VERSION 5.8 ;
BUSBITCHARS "[]" ;
DIVIDERCHAR "/" ;
UNITS
    DATABASE MICRONS 1000 ;
END UNITS

VIA PLL_COUNTER_DCO_PHYS_via1_2_1000_160_1_5_200_200
  VIARULE MET2_MET1 ;
  CUTSIZE 0.09 0.09 ;
  LAYERS MET1 VIA1 MET2 ;
  CUTSPACING 0.11 0.11 ;
  ENCLOSURE 0.04 0.035 0.005 0.04 ;
  ROWCOL 1 5 ;
END PLL_COUNTER_DCO_PHYS_via1_2_1000_160_1_5_200_200

VIA PLL_COUNTER_DCO_PHYS_via2_3_1000_160_1_5_200_200
  VIARULE MET3_MET2 ;
  CUTSIZE 0.09 0.09 ;
  LAYERS MET2 VIA2 MET3 ;
  CUTSPACING 0.11 0.11 ;
  ENCLOSURE 0.005 0.04 0.04 0.005 ;
  ROWCOL 1 5 ;
END PLL_COUNTER_DCO_PHYS_via2_3_1000_160_1_5_200_200

VIA PLL_COUNTER_DCO_PHYS_via3_4_1000_160_1_5_200_200
  VIARULE MET4_MET3 ;
  CUTSIZE 0.09 0.09 ;
  LAYERS MET3 VIA3 MET4 ;
  CUTSPACING 0.11 0.11 ;
  ENCLOSURE 0.04 0.005 0.055 0.04 ;
  ROWCOL 1 5 ;
END PLL_COUNTER_DCO_PHYS_via3_4_1000_160_1_5_200_200

VIA PLL_COUNTER_DCO_PHYS_via4_5_1000_1000_5_5_200_200
  VIARULE MET5_MET4 ;
  CUTSIZE 0.09 0.09 ;
  LAYERS MET4 VIA4 MET5 ;
  CUTSPACING 0.11 0.11 ;
  ENCLOSURE 0.055 0.02 0.04 0.055 ;
  ROWCOL 5 5 ;
END PLL_COUNTER_DCO_PHYS_via4_5_1000_1000_5_5_200_200

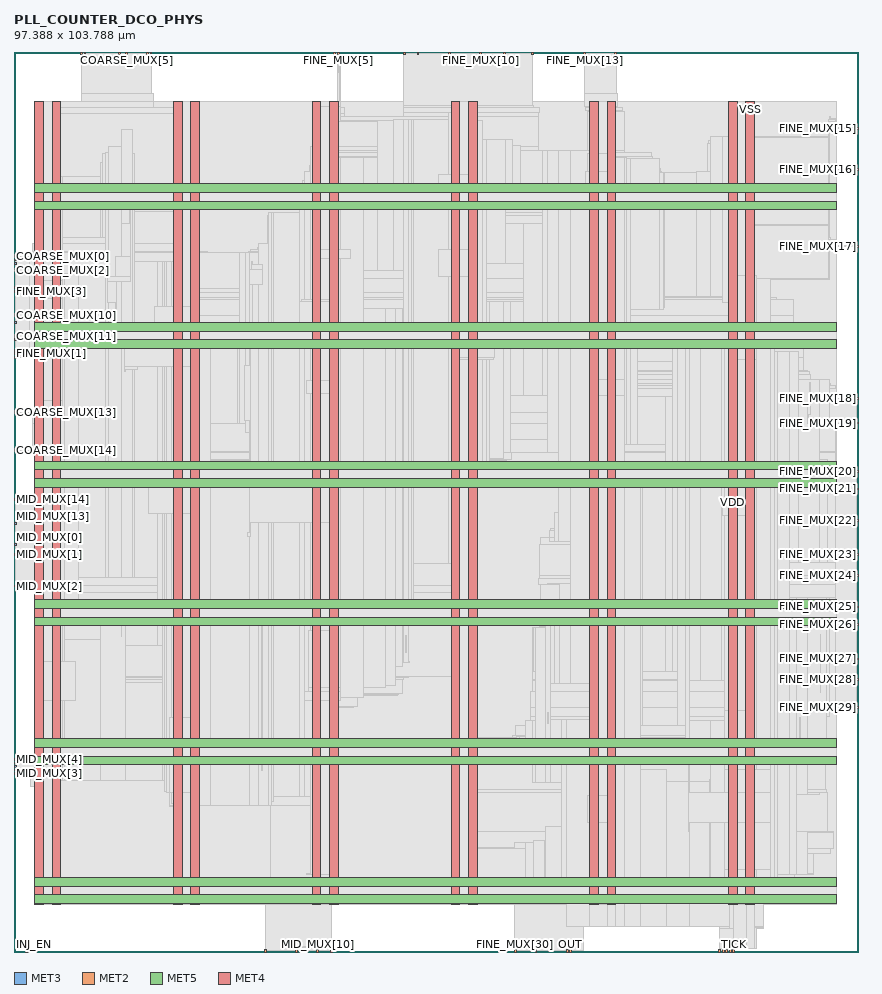
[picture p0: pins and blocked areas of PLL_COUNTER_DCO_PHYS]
MACRO PLL_COUNTER_DCO_PHYS
  FOREIGN PLL_COUNTER_DCO_PHYS 0 0 ;
  CLASS BLOCK ;
  SIZE 97.388 BY 103.788 ;
  PIN COARSE_MUX[0]
    DIRECTION INPUT ;
    USE SIGNAL ;
    PORT
      LAYER MET3 ;
        RECT  0 80.1 0.26 80.3 ;
    END
  END COARSE_MUX[0]
  PIN COARSE_MUX[10]
    DIRECTION INPUT ;
    USE SIGNAL ;
    PORT
      LAYER MET3 ;
        RECT  0 73.3 0.26 73.5 ;
    END
  END COARSE_MUX[10]
  PIN COARSE_MUX[11]
    DIRECTION INPUT ;
    USE SIGNAL ;
    PORT
      LAYER MET3 ;
        RECT  0 70.9 0.26 71.1 ;
    END
  END COARSE_MUX[11]
  PIN COARSE_MUX[12]
    DIRECTION INPUT ;
    USE SIGNAL ;
    PORT
      LAYER MET3 ;
        RECT  0 70.5 0.26 70.7 ;
    END
  END COARSE_MUX[12]
  PIN COARSE_MUX[13]
    DIRECTION INPUT ;
    USE SIGNAL ;
    PORT
      LAYER MET3 ;
        RECT  0 62.1 0.26 62.3 ;
    END
  END COARSE_MUX[13]
  PIN COARSE_MUX[14]
    DIRECTION INPUT ;
    USE SIGNAL ;
    PORT
      LAYER MET3 ;
        RECT  0 57.7 0.26 57.9 ;
    END
  END COARSE_MUX[14]
  PIN COARSE_MUX[1]
    DIRECTION INPUT ;
    USE SIGNAL ;
    PORT
      LAYER MET3 ;
        RECT  0 79.7 0.26 79.9 ;
    END
  END COARSE_MUX[1]
  PIN COARSE_MUX[2]
    DIRECTION INPUT ;
    USE SIGNAL ;
    PORT
      LAYER MET3 ;
        RECT  0 79.3 0.26 79.5 ;
    END
  END COARSE_MUX[2]
  PIN COARSE_MUX[3]
    DIRECTION INPUT ;
    USE SIGNAL ;
    PORT
      LAYER MET2 ;
        RECT  7.7 103.528 7.9 103.788 ;
    END
  END COARSE_MUX[3]
  PIN COARSE_MUX[4]
    DIRECTION INPUT ;
    USE SIGNAL ;
    PORT
      LAYER MET2 ;
        RECT  8.1 103.528 8.3 103.788 ;
    END
  END COARSE_MUX[4]
  PIN COARSE_MUX[5]
    DIRECTION INPUT ;
    USE SIGNAL ;
    PORT
      LAYER MET2 ;
        RECT  12.9 103.528 13.1 103.788 ;
    END
  END COARSE_MUX[5]
  PIN COARSE_MUX[6]
    DIRECTION INPUT ;
    USE SIGNAL ;
    PORT
      LAYER MET2 ;
        RECT  12.1 103.528 12.3 103.788 ;
    END
  END COARSE_MUX[6]
  PIN COARSE_MUX[7]
    DIRECTION INPUT ;
    USE SIGNAL ;
    PORT
      LAYER MET2 ;
        RECT  15.3 103.528 15.5 103.788 ;
    END
  END COARSE_MUX[7]
  PIN COARSE_MUX[8]
    DIRECTION INPUT ;
    USE SIGNAL ;
    PORT
      LAYER MET2 ;
        RECT  15.7 103.528 15.9 103.788 ;
    END
  END COARSE_MUX[8]
  PIN COARSE_MUX[9]
    DIRECTION INPUT ;
    USE SIGNAL ;
    PORT
      LAYER MET3 ;
        RECT  0 72.5 0.26 72.7 ;
    END
  END COARSE_MUX[9]
  PIN DCO_EN
    DIRECTION INPUT ;
    USE SIGNAL ;
    PORT
      LAYER MET2 ;
        RECT  82.5 0 82.7 0.26 ;
    END
  END DCO_EN
  PIN FINE_MUX[0]
    DIRECTION INPUT ;
    USE SIGNAL ;
    PORT
      LAYER MET3 ;
        RECT  0 69.3 0.26 69.5 ;
    END
  END FINE_MUX[0]
  PIN FINE_MUX[10]
    DIRECTION INPUT ;
    USE SIGNAL ;
    PORT
      LAYER MET2 ;
        RECT  53.7 103.528 53.9 103.788 ;
    END
  END FINE_MUX[10]
  PIN FINE_MUX[11]
    DIRECTION INPUT ;
    USE SIGNAL ;
    PORT
      LAYER MET2 ;
        RECT  56.5 103.528 56.7 103.788 ;
    END
  END FINE_MUX[11]
  PIN FINE_MUX[12]
    DIRECTION INPUT ;
    USE SIGNAL ;
    PORT
      LAYER MET2 ;
        RECT  59.7 103.528 59.9 103.788 ;
    END
  END FINE_MUX[12]
  PIN FINE_MUX[13]
    DIRECTION INPUT ;
    USE SIGNAL ;
    PORT
      LAYER MET2 ;
        RECT  65.7 103.528 65.9 103.788 ;
    END
  END FINE_MUX[13]
  PIN FINE_MUX[14]
    DIRECTION INPUT ;
    USE SIGNAL ;
    PORT
      LAYER MET2 ;
        RECT  69.3 103.528 69.5 103.788 ;
    END
  END FINE_MUX[14]
  PIN FINE_MUX[15]
    DIRECTION INPUT ;
    USE SIGNAL ;
    PORT
      LAYER MET3 ;
        RECT  97.128 94.9 97.388 95.1 ;
    END
  END FINE_MUX[15]
  PIN FINE_MUX[16]
    DIRECTION INPUT ;
    USE SIGNAL ;
    PORT
      LAYER MET3 ;
        RECT  97.128 90.1 97.388 90.3 ;
    END
  END FINE_MUX[16]
  PIN FINE_MUX[17]
    DIRECTION INPUT ;
    USE SIGNAL ;
    PORT
      LAYER MET3 ;
        RECT  97.128 81.3 97.388 81.5 ;
    END
  END FINE_MUX[17]
  PIN FINE_MUX[18]
    DIRECTION INPUT ;
    USE SIGNAL ;
    PORT
      LAYER MET3 ;
        RECT  97.128 63.7 97.388 63.9 ;
    END
  END FINE_MUX[18]
  PIN FINE_MUX[19]
    DIRECTION INPUT ;
    USE SIGNAL ;
    PORT
      LAYER MET3 ;
        RECT  97.128 60.9 97.388 61.1 ;
    END
  END FINE_MUX[19]
  PIN FINE_MUX[1]
    DIRECTION INPUT ;
    USE SIGNAL ;
    PORT
      LAYER MET3 ;
        RECT  0 68.9 0.26 69.1 ;
    END
  END FINE_MUX[1]
  PIN FINE_MUX[20]
    DIRECTION INPUT ;
    USE SIGNAL ;
    PORT
      LAYER MET3 ;
        RECT  97.128 55.3 97.388 55.5 ;
    END
  END FINE_MUX[20]
  PIN FINE_MUX[21]
    DIRECTION INPUT ;
    USE SIGNAL ;
    PORT
      LAYER MET3 ;
        RECT  97.128 53.3 97.388 53.5 ;
    END
  END FINE_MUX[21]
  PIN FINE_MUX[22]
    DIRECTION INPUT ;
    USE SIGNAL ;
    PORT
      LAYER MET3 ;
        RECT  97.128 49.7 97.388 49.9 ;
    END
  END FINE_MUX[22]
  PIN FINE_MUX[23]
    DIRECTION INPUT ;
    USE SIGNAL ;
    PORT
      LAYER MET3 ;
        RECT  97.128 45.7 97.388 45.9 ;
    END
  END FINE_MUX[23]
  PIN FINE_MUX[24]
    DIRECTION INPUT ;
    USE SIGNAL ;
    PORT
      LAYER MET3 ;
        RECT  97.128 43.3 97.388 43.5 ;
    END
  END FINE_MUX[24]
  PIN FINE_MUX[25]
    DIRECTION INPUT ;
    USE SIGNAL ;
    PORT
      LAYER MET3 ;
        RECT  97.128 39.7 97.388 39.9 ;
    END
  END FINE_MUX[25]
  PIN FINE_MUX[26]
    DIRECTION INPUT ;
    USE SIGNAL ;
    PORT
      LAYER MET3 ;
        RECT  97.128 37.7 97.388 37.9 ;
    END
  END FINE_MUX[26]
  PIN FINE_MUX[27]
    DIRECTION INPUT ;
    USE SIGNAL ;
    PORT
      LAYER MET3 ;
        RECT  97.128 33.7 97.388 33.9 ;
    END
  END FINE_MUX[27]
  PIN FINE_MUX[28]
    DIRECTION INPUT ;
    USE SIGNAL ;
    PORT
      LAYER MET3 ;
        RECT  97.128 31.3 97.388 31.5 ;
    END
  END FINE_MUX[28]
  PIN FINE_MUX[29]
    DIRECTION INPUT ;
    USE SIGNAL ;
    PORT
      LAYER MET3 ;
        RECT  97.128 28.1 97.388 28.3 ;
    END
  END FINE_MUX[29]
  PIN FINE_MUX[2]
    DIRECTION INPUT ;
    USE SIGNAL ;
    PORT
      LAYER MET3 ;
        RECT  0 68.5 0.26 68.7 ;
    END
  END FINE_MUX[2]
  PIN FINE_MUX[30]
    DIRECTION INPUT ;
    USE SIGNAL ;
    PORT
      LAYER MET2 ;
        RECT  57.7 0 57.9 0.26 ;
    END
  END FINE_MUX[30]
  PIN FINE_MUX[3]
    DIRECTION INPUT ;
    USE SIGNAL ;
    PORT
      LAYER MET3 ;
        RECT  0 76.1 0.26 76.3 ;
    END
  END FINE_MUX[3]
  PIN FINE_MUX[4]
    DIRECTION INPUT ;
    USE SIGNAL ;
    PORT
      LAYER MET3 ;
        RECT  0 76.5 0.26 76.7 ;
    END
  END FINE_MUX[4]
  PIN FINE_MUX[5]
    DIRECTION INPUT ;
    USE SIGNAL ;
    PORT
      LAYER MET2 ;
        RECT  37.3 103.528 37.5 103.788 ;
    END
  END FINE_MUX[5]
  PIN FINE_MUX[6]
    DIRECTION INPUT ;
    USE SIGNAL ;
    PORT
      LAYER MET2 ;
        RECT  36.9 103.528 37.1 103.788 ;
    END
  END FINE_MUX[6]
  PIN FINE_MUX[7]
    DIRECTION INPUT ;
    USE SIGNAL ;
    PORT
      LAYER MET2 ;
        RECT  44.9 103.528 45.1 103.788 ;
    END
  END FINE_MUX[7]
  PIN FINE_MUX[8]
    DIRECTION INPUT ;
    USE SIGNAL ;
    PORT
      LAYER MET2 ;
        RECT  46.5 103.528 46.7 103.788 ;
    END
  END FINE_MUX[8]
  PIN FINE_MUX[9]
    DIRECTION INPUT ;
    USE SIGNAL ;
    PORT
      LAYER MET2 ;
        RECT  50.1 103.528 50.3 103.788 ;
    END
  END FINE_MUX[9]
  PIN INJ_EDGE
    DIRECTION OUTPUT ;
    USE SIGNAL ;
    PORT
      LAYER MET2 ;
        RECT  82.1 0 82.3 0.26 ;
    END
  END INJ_EDGE
  PIN INJ_EN
    DIRECTION INPUT ;
    USE SIGNAL ;
    PORT
      LAYER MET2 ;
        RECT  1.3 0 1.5 0.26 ;
    END
  END INJ_EN
  PIN MID_MUX[0]
    DIRECTION INPUT ;
    USE SIGNAL ;
    PORT
      LAYER MET3 ;
        RECT  0 46.9 0.26 47.1 ;
    END
  END MID_MUX[0]
  PIN MID_MUX[10]
    DIRECTION INPUT ;
    USE SIGNAL ;
    PORT
      LAYER MET2 ;
        RECT  34.9 0 35.1 0.26 ;
    END
  END MID_MUX[10]
  PIN MID_MUX[11]
    DIRECTION INPUT ;
    USE SIGNAL ;
    PORT
      LAYER MET2 ;
        RECT  36.5 0 36.7 0.26 ;
    END
  END MID_MUX[11]
  PIN MID_MUX[12]
    DIRECTION INPUT ;
    USE SIGNAL ;
    PORT
      LAYER MET2 ;
        RECT  32.5 0 32.7 0.26 ;
    END
  END MID_MUX[12]
  PIN MID_MUX[13]
    DIRECTION INPUT ;
    USE SIGNAL ;
    PORT
      LAYER MET3 ;
        RECT  0 49.3 0.26 49.5 ;
    END
  END MID_MUX[13]
  PIN MID_MUX[14]
    DIRECTION INPUT ;
    USE SIGNAL ;
    PORT
      LAYER MET3 ;
        RECT  0 52.1 0.26 52.3 ;
    END
  END MID_MUX[14]
  PIN MID_MUX[1]
    DIRECTION INPUT ;
    USE SIGNAL ;
    PORT
      LAYER MET3 ;
        RECT  0 45.7 0.26 45.9 ;
    END
  END MID_MUX[1]
  PIN MID_MUX[2]
    DIRECTION INPUT ;
    USE SIGNAL ;
    PORT
      LAYER MET3 ;
        RECT  0 42.1 0.26 42.3 ;
    END
  END MID_MUX[2]
  PIN MID_MUX[3]
    DIRECTION INPUT ;
    USE SIGNAL ;
    PORT
      LAYER MET3 ;
        RECT  0 20.5 0.26 20.7 ;
    END
  END MID_MUX[3]
  PIN MID_MUX[4]
    DIRECTION INPUT ;
    USE SIGNAL ;
    PORT
      LAYER MET3 ;
        RECT  0 21.3 0.26 21.5 ;
    END
  END MID_MUX[4]
  PIN MID_MUX[5]
    DIRECTION INPUT ;
    USE SIGNAL ;
    PORT
      LAYER MET3 ;
        RECT  0 22.1 0.26 22.3 ;
    END
  END MID_MUX[5]
  PIN MID_MUX[6]
    DIRECTION INPUT ;
    USE SIGNAL ;
    PORT
      LAYER MET3 ;
        RECT  0 21.7 0.26 21.9 ;
    END
  END MID_MUX[6]
  PIN MID_MUX[7]
    DIRECTION INPUT ;
    USE SIGNAL ;
    PORT
      LAYER MET3 ;
        RECT  0 20.9 0.26 21.1 ;
    END
  END MID_MUX[7]
  PIN MID_MUX[8]
    DIRECTION INPUT ;
    USE SIGNAL ;
    PORT
      LAYER MET2 ;
        RECT  28.9 0 29.1 0.26 ;
    END
  END MID_MUX[8]
  PIN MID_MUX[9]
    DIRECTION INPUT ;
    USE SIGNAL ;
    PORT
      LAYER MET2 ;
        RECT  32.9 0 33.1 0.26 ;
    END
  END MID_MUX[9]
  PIN MID_OUT
    DIRECTION OUTPUT ;
    USE SIGNAL ;
    PORT
      LAYER MET2 ;
        RECT  60.1 0 60.3 0.26 ;
    END
  END MID_OUT
  PIN OUT
    DIRECTION OUTPUT ;
    USE SIGNAL ;
    PORT
      LAYER MET2 ;
        RECT  64.1 0 64.3 0.26 ;
    END
  END OUT
  PIN REF
    DIRECTION INPUT ;
    USE SIGNAL ;
    PORT
      LAYER MET2 ;
        RECT  63.7 0 63.9 0.26 ;
    END
  END REF
  PIN SS_BBPD[0]
    DIRECTION OUTPUT ;
    USE SIGNAL ;
    PORT
      LAYER MET2 ;
        RECT  81.7 0 81.9 0.26 ;
    END
  END SS_BBPD[0]
  PIN SS_BBPD[1]
    DIRECTION OUTPUT ;
    USE SIGNAL ;
    PORT
      LAYER MET2 ;
        RECT  81.3 0 81.5 0.26 ;
    END
  END SS_BBPD[1]
  PIN TICK
    DIRECTION INPUT ;
    USE SIGNAL ;
    PORT
      LAYER MET2 ;
        RECT  82.9 0 83.1 0.26 ;
    END
  END TICK
  PIN VDD
    DIRECTION INOUT ;
    USE POWER ;
    PORT
      LAYER MET5 ;
        RECT  2.4 85.6 94.8 86.6 ;
        RECT  2.4 69.6 94.8 70.6 ;
        RECT  2.4 53.6 94.8 54.6 ;
        RECT  2.4 37.6 94.8 38.6 ;
        RECT  2.4 21.6 94.8 22.6 ;
        RECT  2.4 5.6 94.8 6.6 ;
      LAYER MET4 ;
        RECT  82.4 5.52 83.4 98.08 ;
        RECT  66.4 5.52 67.4 98.08 ;
        RECT  50.4 5.52 51.4 98.08 ;
        RECT  34.4 5.52 35.4 98.08 ;
        RECT  18.4 5.52 19.4 98.08 ;
        RECT  2.4 5.52 3.4 98.08 ;
    END
  END VDD
  PIN VSS
    DIRECTION INOUT ;
    USE GROUND ;
    PORT
      LAYER MET5 ;
        RECT  2.4 87.6 94.8 88.6 ;
        RECT  2.4 71.6 94.8 72.6 ;
        RECT  2.4 55.6 94.8 56.6 ;
        RECT  2.4 39.6 94.8 40.6 ;
        RECT  2.4 23.6 94.8 24.6 ;
        RECT  2.4 7.6 94.8 8.6 ;
      LAYER MET4 ;
        RECT  84.4 5.515 85.4 98.085 ;
        RECT  68.4 5.515 69.4 98.085 ;
        RECT  52.4 5.515 53.4 98.085 ;
        RECT  36.4 5.515 37.4 98.085 ;
        RECT  20.4 5.515 21.4 98.085 ;
        RECT  4.4 5.515 5.4 98.085 ;
    END
  END VSS
  OBS
    LAYER MET1 ;
     RECT  2.4 5.52 94.8 98.08 ;
    LAYER MET2 ;
     RECT  64.55 0.15 65.65 0.2 ;
     RECT  81.35 0.2 83.05 0.35 ;
     RECT  81.35 0.35 85.65 2.75 ;
     RECT  81.35 2.75 86.45 2.95 ;
     RECT  28.95 0.2 36.65 5.515 ;
     RECT  57.75 0.2 65.65 5.515 ;
     RECT  77.75 2.95 86.45 5.78 ;
     RECT  57.75 5.515 69.35 5.95 ;
     RECT  77.75 5.78 86.95 5.95 ;
     RECT  28.95 5.515 37.35 6.15 ;
     RECT  57.75 5.95 70.05 6.15 ;
     RECT  29.05 6.15 37.35 6.56 ;
     RECT  57.85 6.15 71.45 6.56 ;
     RECT  58.45 6.56 71.45 6.76 ;
     RECT  4.45 5.515 5.35 6.915 ;
     RECT  20.45 5.515 21.35 6.915 ;
     RECT  52.45 5.515 53.35 6.915 ;
     RECT  77.75 5.95 87.05 7.15 ;
     RECT  76.65 7.15 87.05 7.24 ;
     RECT  58.95 6.76 71.45 7.365 ;
     RECT  76.25 7.24 87.05 7.365 ;
     RECT  58.95 7.365 87.05 7.44 ;
     RECT  58.95 7.44 87.95 7.84 ;
     RECT  58.95 7.84 89.75 7.95 ;
     RECT  58.95 7.95 90.05 8.95 ;
     RECT  58.95 8.95 92.25 11.38 ;
     RECT  50.45 6.915 53.35 11.95 ;
     RECT  58.95 11.38 94.15 11.95 ;
     RECT  50.45 11.95 94.45 13.85 ;
     RECT  18.45 6.915 21.35 16.75 ;
     RECT  17.95 16.75 21.35 16.95 ;
     RECT  29.55 6.56 37.35 16.95 ;
     RECT  17.95 16.95 37.35 18.44 ;
     RECT  50.45 13.85 93.85 18.45 ;
     RECT  17.65 18.44 37.35 18.55 ;
     RECT  50.45 18.45 93.65 18.75 ;
     RECT  2.45 6.915 5.35 19.05 ;
     RECT  9.95 19.75 10.65 19.825 ;
     RECT  1.95 19.05 5.35 20.025 ;
     RECT  9.95 19.825 11.35 20.025 ;
     RECT  1.95 20.025 5.75 20.03 ;
     RECT  9.95 20.025 12.35 20.03 ;
     RECT  17.35 18.55 37.35 20.03 ;
     RECT  1.95 20.03 37.35 20.65 ;
     RECT  2.15 20.65 37.35 21.55 ;
     RECT  2.35 21.55 37.35 22.95 ;
     RECT  50.45 18.75 93.55 23.25 ;
     RECT  50.45 23.25 93.65 24.77 ;
     RECT  57.45 24.77 93.65 24.97 ;
     RECT  57.85 24.97 93.65 26.16 ;
     RECT  58.95 26.16 93.65 26.65 ;
     RECT  59.55 26.65 93.65 27.15 ;
     RECT  59.55 27.15 94.05 28.15 ;
     RECT  2.45 22.95 37.35 28.225 ;
     RECT  2.45 28.225 39.15 28.35 ;
     RECT  2.45 28.35 39.65 29.35 ;
     RECT  2.45 29.35 40.25 29.55 ;
     RECT  2.45 29.55 44.25 29.75 ;
     RECT  2.45 29.75 44.35 29.84 ;
     RECT  59.55 28.15 94.85 30.05 ;
     RECT  59.75 30.05 94.85 31.35 ;
     RECT  2.45 29.84 44.75 31.43 ;
     RECT  59.75 31.35 95.05 31.45 ;
     RECT  2.45 31.43 44.95 31.64 ;
     RECT  2.45 31.64 45.55 31.75 ;
     RECT  50.45 24.77 53.35 31.75 ;
     RECT  59.75 31.45 94.85 37.45 ;
     RECT  60.65 37.45 94.85 37.56 ;
     RECT  60.75 37.56 94.85 39.75 ;
     RECT  60.75 39.75 95.05 39.85 ;
     RECT  2.45 31.75 53.35 41.45 ;
     RECT  2.35 41.45 53.35 42.25 ;
     RECT  60.75 39.85 94.85 42.425 ;
     RECT  60.45 42.425 94.85 43.05 ;
     RECT  60.55 43.05 94.85 43.45 ;
     RECT  2.45 42.25 53.35 46.95 ;
     RECT  60.65 43.45 94.85 46.975 ;
     RECT  60.75 46.975 94.85 47.85 ;
     RECT  61.75 47.85 94.85 48.65 ;
     RECT  61.85 48.65 94.85 48.82 ;
     RECT  62.35 48.82 94.85 50.65 ;
     RECT  2.15 46.95 53.35 52.35 ;
     RECT  2.45 52.35 53.35 55.04 ;
     RECT  2.45 55.04 55.55 55.24 ;
     RECT  2.45 55.24 55.75 55.55 ;
     RECT  62.75 50.65 94.85 56.55 ;
     RECT  2.45 55.55 56.25 56.63 ;
     RECT  2.45 56.63 56.75 56.84 ;
     RECT  2.45 56.84 57.35 57.55 ;
     RECT  62.75 56.55 94.75 57.55 ;
     RECT  2.45 57.55 94.75 57.75 ;
     RECT  2.15 57.75 94.75 60.95 ;
     RECT  2.15 60.95 94.85 62.25 ;
     RECT  2.45 62.25 94.85 64.95 ;
     RECT  2.45 64.95 94.75 65.36 ;
     RECT  2.45 65.36 94.15 65.56 ;
     RECT  2.45 65.56 94.05 66.05 ;
     RECT  2.45 66.05 91.85 66.65 ;
     RECT  2.45 66.65 91.75 66.975 ;
     RECT  2.45 66.975 91.55 67.05 ;
     RECT  2.45 67.05 91.05 68.55 ;
     RECT  2.15 68.55 91.05 69.65 ;
     RECT  2.15 69.65 90.75 69.82 ;
     RECT  2.15 69.82 89.95 69.85 ;
     RECT  2.15 69.85 89.85 70.95 ;
     RECT  1.95 70.95 89.85 73.35 ;
     RECT  2.15 73.35 89.85 75.25 ;
     RECT  2.15 75.25 87.95 75.42 ;
     RECT  2.15 75.42 85.85 76.05 ;
     RECT  2.15 76.05 85.65 77.65 ;
     RECT  2.15 77.65 85.35 80.65 ;
     RECT  2.15 80.65 22.35 80.77 ;
     RECT  27.05 80.65 85.35 80.775 ;
     RECT  27.25 80.775 85.35 80.97 ;
     RECT  27.85 80.97 85.35 80.975 ;
     RECT  28.05 80.975 85.35 81.25 ;
     RECT  93.95 77.55 94.05 81.35 ;
     RECT  28.15 81.25 85.35 81.65 ;
     RECT  2.15 80.77 21.35 81.75 ;
     RECT  93.95 81.35 94.85 81.75 ;
     RECT  93.95 81.75 94.75 82.16 ;
     RECT  93.95 82.16 94.15 82.36 ;
     RECT  29.25 81.65 85.35 84.96 ;
     RECT  29.35 84.96 85.35 85.25 ;
     RECT  32.95 85.25 85.35 88.45 ;
     RECT  33.25 88.45 85.35 88.975 ;
     RECT  33.55 88.975 85.35 89.65 ;
     RECT  33.55 89.65 74.65 89.95 ;
     RECT  93.95 82.36 94.05 90.03 ;
     RECT  34.05 89.95 74.65 90.05 ;
     RECT  78.75 89.65 85.35 90.05 ;
     RECT  93.95 90.03 94.75 90.15 ;
     RECT  93.95 90.15 95.05 90.25 ;
     RECT  34.05 90.05 74.55 90.36 ;
     RECT  93.95 90.25 94.75 90.56 ;
     RECT  34.05 90.36 74.45 90.65 ;
     RECT  93.95 90.56 94.15 90.76 ;
     RECT  34.15 90.65 74.45 91.45 ;
     RECT  34.15 91.45 73.65 91.75 ;
     RECT  34.15 91.75 73.55 92.17 ;
     RECT  34.15 92.17 70.45 92.45 ;
     RECT  34.15 92.45 60.45 92.85 ;
     RECT  79.95 90.05 85.35 93.25 ;
     RECT  80.05 93.25 85.35 93.56 ;
     RECT  80.35 93.56 85.35 94.05 ;
     RECT  93.95 90.76 94.05 94.95 ;
     RECT  93.95 94.95 94.85 95.75 ;
     RECT  93.95 95.75 94.75 95.95 ;
     RECT  94.05 95.95 94.75 96.16 ;
     RECT  34.45 92.85 60.45 96.36 ;
     RECT  94.05 96.16 94.15 96.36 ;
     RECT  2.45 81.75 21.35 96.685 ;
     RECT  34.45 96.36 38.15 96.685 ;
     RECT  82.45 94.05 85.35 96.685 ;
     RECT  44.95 96.36 60.45 96.84 ;
     RECT  66.15 92.45 70.45 96.95 ;
     RECT  66.15 96.95 70.15 97.04 ;
     RECT  4.45 96.685 21.35 97.375 ;
     RECT  36.45 96.685 38.15 97.375 ;
     RECT  44.95 96.84 60.55 97.375 ;
     RECT  65.85 97.04 70.15 97.375 ;
     RECT  65.85 97.375 69.65 97.45 ;
     RECT  44.95 97.375 59.95 97.57 ;
     RECT  4.45 97.375 16.05 98.085 ;
     RECT  20.45 97.375 21.35 98.085 ;
     RECT  36.45 97.375 37.65 98.085 ;
     RECT  84.45 96.685 85.35 98.085 ;
     RECT  7.75 98.085 16.05 99.05 ;
     RECT  65.75 97.45 69.65 99.05 ;
     RECT  37.35 98.085 37.65 101.45 ;
     RECT  37.35 101.45 37.45 103.35 ;
     RECT  7.75 99.05 15.85 103.6 ;
     RECT  36.95 103.35 37.45 103.6 ;
     RECT  44.95 97.57 59.85 103.6 ;
     RECT  65.75 99.05 69.45 103.6 ;
    LAYER MET3 ;
     RECT  0.2 68.55 1.75 80.25 ;
     RECT  0.2 20.55 2.415 22.25 ;
     RECT  0.2 42.15 2.415 52.25 ;
     RECT  0.2 57.75 2.415 57.85 ;
     RECT  0.2 62.15 2.415 62.25 ;
     RECT  1.75 68.55 2.415 80.45 ;
     RECT  2.415 6.95 4.415 96.65 ;
     RECT  4.415 5.55 5.385 98.05 ;
     RECT  5.385 19.75 5.65 89.45 ;
     RECT  5.65 19.75 5.85 78.25 ;
     RECT  5.85 40.55 7.45 78.25 ;
     RECT  5.85 19.75 9.95 36.05 ;
     RECT  5.65 82.35 9.95 89.45 ;
     RECT  9.95 82.35 10.15 91.05 ;
     RECT  7.45 43.15 10.55 78.25 ;
     RECT  10.15 82.35 10.55 92.05 ;
     RECT  10.55 43.15 10.95 92.25 ;
     RECT  10.95 43.15 12.35 92.85 ;
     RECT  9.95 19.75 12.85 39.05 ;
     RECT  12.35 43.15 13.65 94.85 ;
     RECT  13.65 43.15 13.85 92.05 ;
     RECT  12.85 35.35 16.55 39.05 ;
     RECT  13.85 43.15 16.55 79.65 ;
     RECT  12.85 19.75 17.15 31.05 ;
     RECT  16.55 35.35 17.15 79.65 ;
     RECT  17.15 19.75 17.35 79.65 ;
     RECT  17.35 18.55 17.565 79.65 ;
     RECT  17.565 18.35 18.15 79.65 ;
     RECT  18.15 17.15 18.415 79.65 ;
     RECT  13.85 85.35 18.415 87.05 ;
     RECT  18.415 6.95 20.415 96.65 ;
     RECT  20.415 5.55 21.385 98.05 ;
     RECT  21.385 16.95 22.65 70.85 ;
     RECT  22.65 60.95 25.75 70.85 ;
     RECT  25.75 60.95 25.95 71.45 ;
     RECT  21.385 76.55 25.95 80.65 ;
     RECT  25.95 60.95 26.75 80.65 ;
     RECT  22.65 16.95 27.15 55.85 ;
     RECT  26.75 59.95 27.15 80.65 ;
     RECT  27.15 16.95 28.15 80.65 ;
     RECT  28.15 16.95 29.35 81.65 ;
     RECT  29.35 16.95 29.65 85.25 ;
     RECT  29.65 17.35 29.95 85.25 ;
     RECT  29.95 17.95 32.95 85.25 ;
     RECT  32.95 17.95 33.55 88.45 ;
     RECT  32.55 0.55 34.05 0.65 ;
     RECT  33.55 17.95 34.15 89.95 ;
     RECT  33.765 8.95 34.415 9.05 ;
     RECT  34.15 17.95 34.415 92.85 ;
     RECT  34.415 6.95 36.415 96.65 ;
     RECT  36.415 5.55 37.385 98.05 ;
     RECT  37.385 28.95 37.65 91.65 ;
     RECT  37.385 95.75 37.65 97.65 ;
     RECT  36.95 103.35 37.65 103.45 ;
     RECT  37.65 29.35 40.25 91.65 ;
     RECT  40.25 78.55 41.95 91.65 ;
     RECT  37.65 95.75 41.95 95.85 ;
     RECT  40.25 30.55 42.85 74.25 ;
     RECT  41.95 78.55 43.75 95.85 ;
     RECT  42.85 30.75 44.05 74.25 ;
     RECT  44.05 32.95 44.85 74.25 ;
     RECT  44.85 33.35 44.95 74.25 ;
     RECT  43.75 78.55 44.95 96.05 ;
     RECT  44.95 33.35 45.55 96.05 ;
     RECT  45.55 33.35 45.65 33.45 ;
     RECT  45.55 37.75 45.85 96.05 ;
     RECT  45.85 38.95 46.05 96.05 ;
     RECT  46.05 44.75 50.15 96.05 ;
     RECT  46.05 38.95 50.415 40.65 ;
     RECT  50.15 44.75 50.415 96.85 ;
     RECT  50.415 6.95 50.55 96.85 ;
     RECT  50.55 6.95 52.415 97.05 ;
     RECT  52.415 5.55 53.385 98.05 ;
     RECT  53.385 55.35 54.05 95.85 ;
     RECT  54.05 55.35 54.45 93.65 ;
     RECT  54.45 56.15 54.85 75.05 ;
     RECT  54.85 56.95 56.45 75.05 ;
     RECT  54.45 79.35 56.65 93.65 ;
     RECT  56.45 57.55 57.25 75.05 ;
     RECT  56.65 88.15 57.45 93.65 ;
     RECT  53.385 11.95 57.75 12.05 ;
     RECT  53.385 22.55 57.95 24.05 ;
     RECT  57.95 22.55 58.35 24.85 ;
     RECT  57.45 88.15 58.45 93.05 ;
     RECT  57.25 64.15 58.75 75.05 ;
     RECT  56.65 79.35 58.75 84.05 ;
     RECT  58.75 6.35 58.95 6.45 ;
     RECT  57.75 11.95 58.95 12.65 ;
     RECT  58.35 22.15 58.95 24.85 ;
     RECT  58.95 22.15 59.75 26.65 ;
     RECT  58.95 6.35 59.95 12.65 ;
     RECT  59.75 32.35 59.95 32.45 ;
     RECT  59.75 19.55 60.15 26.65 ;
     RECT  59.95 32.35 60.15 37.45 ;
     RECT  58.75 64.15 60.95 84.05 ;
     RECT  58.45 88.15 60.95 92.45 ;
     RECT  59.95 6.35 61.15 12.85 ;
     RECT  61.15 6.15 61.35 12.85 ;
     RECT  60.15 19.55 61.35 37.45 ;
     RECT  57.25 57.55 61.55 59.05 ;
     RECT  60.95 64.15 61.55 92.45 ;
     RECT  60.75 47.75 61.75 47.85 ;
     RECT  61.35 19.55 61.835 37.65 ;
     RECT  61.835 30.95 62.35 37.65 ;
     RECT  61.75 47.35 62.35 47.85 ;
     RECT  62.35 47.35 62.75 50.65 ;
     RECT  61.55 57.55 62.75 92.45 ;
     RECT  62.35 30.95 62.95 37.85 ;
     RECT  61.55 42.35 62.95 42.45 ;
     RECT  61.35 6.15 63.15 14.45 ;
     RECT  61.835 19.55 63.15 26.85 ;
     RECT  63.15 6.15 63.75 26.85 ;
     RECT  62.95 30.95 64.15 42.45 ;
     RECT  62.75 47.35 64.15 92.45 ;
     RECT  63.75 2.95 66.415 26.85 ;
     RECT  64.15 30.95 66.415 92.45 ;
     RECT  66.415 2.95 68.415 96.65 ;
     RECT  68.415 2.95 69.385 98.05 ;
     RECT  69.385 2.95 70.45 91.65 ;
     RECT  70.45 58.55 70.65 91.65 ;
     RECT  70.65 58.55 71.05 91.45 ;
     RECT  71.05 58.55 71.85 69.65 ;
     RECT  70.45 2.95 72.25 54.05 ;
     RECT  72.25 26.15 72.45 54.05 ;
     RECT  71.05 74.15 74.45 91.45 ;
     RECT  74.45 74.15 74.85 89.85 ;
     RECT  74.85 74.35 75.05 89.85 ;
     RECT  72.45 32.35 75.15 54.05 ;
     RECT  71.85 58.55 75.15 64.05 ;
     RECT  72.25 2.95 75.25 21.05 ;
     RECT  75.15 32.35 75.95 64.05 ;
     RECT  71.85 68.15 75.95 69.65 ;
     RECT  72.45 26.15 76.55 28.25 ;
     RECT  75.95 32.35 76.55 69.65 ;
     RECT  76.55 26.15 77.45 69.65 ;
     RECT  75.25 2.95 77.85 19.65 ;
     RECT  77.45 23.95 77.85 69.65 ;
     RECT  75.05 75.55 78.75 89.85 ;
     RECT  77.85 31.35 79.15 69.65 ;
     RECT  77.85 6.35 80.15 19.65 ;
     RECT  80.15 6.35 80.35 19.85 ;
     RECT  77.85 23.95 80.35 26.65 ;
     RECT  78.75 75.55 80.35 90.05 ;
     RECT  79.15 31.35 81.55 69.85 ;
     RECT  80.35 75.55 81.75 94.05 ;
     RECT  80.35 6.35 81.95 26.65 ;
     RECT  81.55 31.35 81.95 70.25 ;
     RECT  81.95 6.35 82.415 70.25 ;
     RECT  81.75 74.95 82.415 94.05 ;
     RECT  82.415 6.35 82.55 96.65 ;
     RECT  82.55 2.75 82.95 96.65 ;
     RECT  82.95 0.35 84.415 96.65 ;
     RECT  84.415 0.35 85.385 98.05 ;
     RECT  85.385 0.35 85.65 2.85 ;
     RECT  85.385 7.15 85.65 78.05 ;
     RECT  85.65 2.75 86.45 2.85 ;
     RECT  85.65 8.15 87.25 77.65 ;
     RECT  87.25 8.15 87.65 71.05 ;
     RECT  87.65 8.15 88.05 69.25 ;
     RECT  88.05 8.95 89.45 69.25 ;
     RECT  89.45 8.95 90.25 40.85 ;
     RECT  89.45 44.95 90.45 69.25 ;
     RECT  90.25 8.95 91.45 13.85 ;
     RECT  90.25 18.15 91.45 40.85 ;
     RECT  91.45 8.95 92.25 9.05 ;
     RECT  91.45 18.15 92.85 18.45 ;
     RECT  90.45 44.95 92.85 66.05 ;
     RECT  92.85 18.35 93.65 18.45 ;
     RECT  91.45 23.55 93.65 40.85 ;
     RECT  92.85 44.95 93.85 56.85 ;
     RECT  93.65 27.15 94.05 40.85 ;
     RECT  92.85 60.95 94.05 66.05 ;
     RECT  87.25 77.55 94.05 77.65 ;
     RECT  85.385 83.75 94.05 83.85 ;
     RECT  85.385 93.95 94.05 94.05 ;
     RECT  91.45 13.75 94.45 13.85 ;
     RECT  94.05 28.15 94.75 40.85 ;
     RECT  93.85 44.95 94.75 55.45 ;
     RECT  94.75 28.15 97.2 55.45 ;
     RECT  94.05 60.95 97.2 63.85 ;
     RECT  94.75 81.35 97.2 81.45 ;
     RECT  94.95 90.15 97.2 90.25 ;
     RECT  94.75 94.95 97.2 95.05 ;
    LAYER MET4 ;
     RECT  4.4 5.515 5.4 5.52 ;
     RECT  20.4 5.515 21.4 5.52 ;
     RECT  36.4 5.515 37.4 5.52 ;
     RECT  52.4 5.515 53.4 5.52 ;
     RECT  68.4 5.515 69.4 5.52 ;
     RECT  84.4 5.515 85.4 5.52 ;
     RECT  82.4 5.52 85.4 6.35 ;
     RECT  81.95 6.35 85.4 7.95 ;
     RECT  34.4 5.52 37.4 8.95 ;
     RECT  81.95 7.95 85.65 9.55 ;
     RECT  66.4 5.52 69.4 14.95 ;
     RECT  77.75 13.95 77.85 14.95 ;
     RECT  81.95 9.55 87.25 14.95 ;
     RECT  66.15 14.95 69.4 18.05 ;
     RECT  18.4 5.52 21.4 18.35 ;
     RECT  77.75 14.95 87.25 18.45 ;
     RECT  81.95 18.45 87.25 21.05 ;
     RECT  77.75 18.45 77.85 24.05 ;
     RECT  34.15 8.95 37.4 24.15 ;
     RECT  17.95 18.35 21.4 27.05 ;
     RECT  90.55 23.95 90.65 27.05 ;
     RECT  61.55 26.35 61.65 27.65 ;
     RECT  81.95 21.05 85.4 27.85 ;
     RECT  2.4 5.52 5.4 28.95 ;
     RECT  33.55 24.15 37.4 28.95 ;
     RECT  33.55 28.95 37.65 30.05 ;
     RECT  33.95 30.05 37.65 30.45 ;
     RECT  2.4 28.95 7.05 33.45 ;
     RECT  45.15 34.55 45.25 36.45 ;
     RECT  92.95 29.95 93.05 36.65 ;
     RECT  33.95 30.45 37.4 37.05 ;
     RECT  12.35 36.35 12.45 37.85 ;
     RECT  2.4 33.45 5.65 38.75 ;
     RECT  28.55 20.95 28.65 39.25 ;
     RECT  26.95 47.95 27.25 48.32 ;
     RECT  27.15 48.32 27.25 49.55 ;
     RECT  34.4 37.05 37.4 49.55 ;
     RECT  82.4 27.85 85.4 50.35 ;
     RECT  18.4 27.05 21.4 50.55 ;
     RECT  81.75 50.35 85.4 51.65 ;
     RECT  15.55 50.55 21.4 54.05 ;
     RECT  27.15 49.55 37.4 54.05 ;
     RECT  27.15 54.05 28.45 54.85 ;
     RECT  18.4 54.05 21.4 55.15 ;
     RECT  18.4 55.15 21.65 56.05 ;
     RECT  27.15 54.85 27.25 61.35 ;
     RECT  91.55 60.95 91.65 61.95 ;
     RECT  2.4 38.75 5.85 62.05 ;
     RECT  91.55 61.95 91.85 63.05 ;
     RECT  2.4 62.05 5.65 63.65 ;
     RECT  66.4 18.05 69.4 64.15 ;
     RECT  34.4 54.05 37.4 64.35 ;
     RECT  91.75 63.05 91.85 65.65 ;
     RECT  33.75 64.35 37.4 65.85 ;
     RECT  66.4 64.15 70.45 66.05 ;
     RECT  12.75 66.95 12.85 67.15 ;
     RECT  12.75 67.15 14.25 67.55 ;
     RECT  18.4 56.05 21.4 67.55 ;
     RECT  26.55 61.35 27.25 67.65 ;
     RECT  50.4 5.52 53.4 68.35 ;
     RECT  82.4 51.65 85.4 68.35 ;
     RECT  50.4 68.35 55.25 68.55 ;
     RECT  66.4 66.05 69.4 69.75 ;
     RECT  50.4 68.55 55.45 69.85 ;
     RECT  50.4 69.85 55.25 70.05 ;
     RECT  12.75 67.55 21.4 70.25 ;
     RECT  34.15 65.85 37.4 71.15 ;
     RECT  27.15 67.65 27.25 71.35 ;
     RECT  33.15 71.15 37.4 71.35 ;
     RECT  64.35 69.75 69.4 72.65 ;
     RECT  16.15 70.25 21.4 74.45 ;
     RECT  11.75 71.95 11.85 74.95 ;
     RECT  32.95 71.35 37.4 75.05 ;
     RECT  33.15 75.05 37.4 75.25 ;
     RECT  2.4 63.65 5.4 75.35 ;
     RECT  27.15 71.35 27.45 76.95 ;
     RECT  10.75 74.95 11.85 77.35 ;
     RECT  2.4 75.35 5.65 77.45 ;
     RECT  10.75 77.35 13.45 77.85 ;
     RECT  50.4 70.05 53.4 77.95 ;
     RECT  82.4 68.35 85.65 78.05 ;
     RECT  27.15 76.95 28.65 78.65 ;
     RECT  27.35 78.65 28.65 79.25 ;
     RECT  27.35 79.25 27.45 79.65 ;
     RECT  34.4 75.25 37.4 79.95 ;
     RECT  11.75 77.85 13.45 80.25 ;
     RECT  34.4 79.95 38.85 81.05 ;
     RECT  48.95 77.95 53.4 81.05 ;
     RECT  12.35 80.25 13.45 84.05 ;
     RECT  50.4 81.05 53.4 86.95 ;
     RECT  66.4 72.65 69.4 86.95 ;
     RECT  13.35 84.05 13.45 87.05 ;
     RECT  49.55 86.95 53.4 87.95 ;
     RECT  48.95 87.95 53.4 89.65 ;
     RECT  65.95 86.95 69.4 90.05 ;
     RECT  66.15 90.05 69.4 92.05 ;
     RECT  34.4 81.05 37.4 97.55 ;
     RECT  2.4 77.45 5.4 98.08 ;
     RECT  18.4 74.45 21.4 98.08 ;
     RECT  34.4 97.55 37.65 98.08 ;
     RECT  50.4 89.65 53.4 98.08 ;
     RECT  66.4 92.05 69.4 98.08 ;
     RECT  82.4 78.05 85.4 98.08 ;
     RECT  4.4 98.08 5.4 98.085 ;
     RECT  20.4 98.08 21.4 98.085 ;
     RECT  36.4 98.08 37.65 98.085 ;
     RECT  52.4 98.08 53.4 98.085 ;
     RECT  68.4 98.08 69.4 98.085 ;
     RECT  84.4 98.08 85.4 98.085 ;
     RECT  37.55 98.085 37.65 103.45 ;
    LAYER MET5 ;
     RECT  2.4 5.6 94.8 8.6 ;
     RECT  2.4 21.6 94.8 24.6 ;
     RECT  2.4 37.6 94.8 40.6 ;
     RECT  2.4 53.6 94.8 56.6 ;
     RECT  2.4 69.6 94.8 72.6 ;
     RECT  2.4 85.6 94.8 88.6 ;
  END
END PLL_COUNTER_DCO_PHYS
END LIBRARY
